VERSION 5.7 ;
  NOWIREEXTENSIONATPIN ON ;
  DIVIDERCHAR "/" ;
  BUSBITCHARS "[]" ;
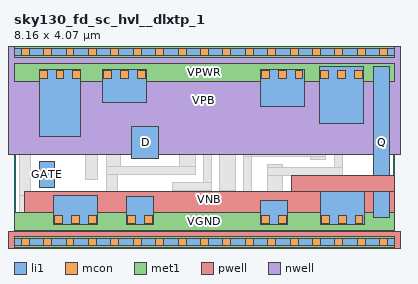
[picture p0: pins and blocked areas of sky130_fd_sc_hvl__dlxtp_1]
MACRO sky130_fd_sc_hvl__dlxtp_1
  CLASS BLOCK ;
  FOREIGN sky130_fd_sc_hvl__dlxtp_1 ;
  ORIGIN 0.000 0.000 ;
  SIZE 8.160 BY 4.070 ;
  PIN D
    ANTENNAGATEAREA 0.585000 ;
    PORT
      LAYER li1 ;
        RECT 2.525 1.795 3.100 2.465 ;
    END
  END D
  PIN GATE
    ANTENNAGATEAREA 0.585000 ;
    PORT
      LAYER li1 ;
        RECT 0.540 1.175 0.870 1.725 ;
    END
  END GATE
  PIN VGND
    USE GROUND ;
    PORT
      LAYER li1 ;
        RECT 0.845 0.365 1.795 0.995 ;
        RECT 2.405 0.365 2.995 0.975 ;
        RECT 5.270 0.365 5.860 0.895 ;
        RECT 6.555 0.365 7.505 1.245 ;
      LAYER mcon ;
        RECT 0.875 0.395 1.045 0.565 ;
        RECT 1.235 0.395 1.405 0.565 ;
        RECT 1.595 0.395 1.765 0.565 ;
        RECT 2.435 0.395 2.605 0.565 ;
        RECT 2.795 0.395 2.965 0.565 ;
        RECT 5.300 0.395 5.470 0.565 ;
        RECT 5.660 0.395 5.830 0.565 ;
        RECT 6.585 0.395 6.755 0.565 ;
        RECT 6.945 0.395 7.115 0.565 ;
        RECT 7.305 0.395 7.475 0.565 ;
      LAYER met1 ;
        RECT 0.000 0.255 8.160 0.625 ;
    END
  END VGND
  PIN VNB
    ANTENNADIFFAREA 1.387200 ;
    PORT
      LAYER pwell ;
        RECT 5.955 1.085 8.140 1.415 ;
        RECT 0.225 0.215 8.140 1.085 ;
        RECT -0.130 -0.215 8.290 0.215 ;
      LAYER li1 ;
        RECT 0.000 -0.085 8.160 0.085 ;
      LAYER mcon ;
        RECT 0.155 -0.085 0.325 0.085 ;
        RECT 0.635 -0.085 0.805 0.085 ;
        RECT 1.115 -0.085 1.285 0.085 ;
        RECT 1.595 -0.085 1.765 0.085 ;
        RECT 2.075 -0.085 2.245 0.085 ;
        RECT 2.555 -0.085 2.725 0.085 ;
        RECT 3.035 -0.085 3.205 0.085 ;
        RECT 3.515 -0.085 3.685 0.085 ;
        RECT 3.995 -0.085 4.165 0.085 ;
        RECT 4.475 -0.085 4.645 0.085 ;
        RECT 4.955 -0.085 5.125 0.085 ;
        RECT 5.435 -0.085 5.605 0.085 ;
        RECT 5.915 -0.085 6.085 0.085 ;
        RECT 6.395 -0.085 6.565 0.085 ;
        RECT 6.875 -0.085 7.045 0.085 ;
        RECT 7.355 -0.085 7.525 0.085 ;
        RECT 7.835 -0.085 8.005 0.085 ;
      LAYER met1 ;
        RECT 0.000 -0.115 8.160 0.115 ;
    END
  END VNB
  PIN VPB
    ANTENNADIFFAREA 1.387200 ;
    PORT
      LAYER nwell ;
        RECT -0.330 1.885 8.490 4.485 ;
      LAYER li1 ;
        RECT 0.000 3.985 8.160 4.155 ;
      LAYER mcon ;
        RECT 0.155 3.985 0.325 4.155 ;
        RECT 0.635 3.985 0.805 4.155 ;
        RECT 1.115 3.985 1.285 4.155 ;
        RECT 1.595 3.985 1.765 4.155 ;
        RECT 2.075 3.985 2.245 4.155 ;
        RECT 2.555 3.985 2.725 4.155 ;
        RECT 3.035 3.985 3.205 4.155 ;
        RECT 3.515 3.985 3.685 4.155 ;
        RECT 3.995 3.985 4.165 4.155 ;
        RECT 4.475 3.985 4.645 4.155 ;
        RECT 4.955 3.985 5.125 4.155 ;
        RECT 5.435 3.985 5.605 4.155 ;
        RECT 5.915 3.985 6.085 4.155 ;
        RECT 6.395 3.985 6.565 4.155 ;
        RECT 6.875 3.985 7.045 4.155 ;
        RECT 7.355 3.985 7.525 4.155 ;
        RECT 7.835 3.985 8.005 4.155 ;
      LAYER met1 ;
        RECT 0.000 3.955 8.160 4.185 ;
    END
  END VPB
  PIN VPWR
    USE POWER ;
    PORT
      LAYER li1 ;
        RECT 0.540 2.255 1.430 3.705 ;
        RECT 1.890 2.995 2.840 3.705 ;
        RECT 5.270 2.895 6.220 3.705 ;
        RECT 6.535 2.535 7.485 3.755 ;
      LAYER mcon ;
        RECT 0.540 3.505 0.710 3.675 ;
        RECT 0.900 3.505 1.070 3.675 ;
        RECT 1.260 3.505 1.430 3.675 ;
        RECT 1.920 3.505 2.090 3.675 ;
        RECT 2.280 3.505 2.450 3.675 ;
        RECT 2.640 3.505 2.810 3.675 ;
        RECT 5.300 3.505 5.470 3.675 ;
        RECT 5.660 3.505 5.830 3.675 ;
        RECT 6.020 3.505 6.190 3.675 ;
        RECT 6.565 3.505 6.735 3.675 ;
        RECT 6.925 3.505 7.095 3.675 ;
        RECT 7.285 3.505 7.455 3.675 ;
      LAYER met1 ;
        RECT 0.000 3.445 8.160 3.815 ;
    END
  END VPWR
  PIN Q
    ANTENNADIFFAREA 0.626250 ;
    PORT
      LAYER li1 ;
        RECT 7.700 0.515 8.050 3.755 ;
    END
  END Q
  OBS
      LAYER li1 ;
        RECT 3.020 3.635 4.050 3.805 ;
        RECT 0.110 2.075 0.360 2.985 ;
        RECT 3.020 2.815 3.190 3.635 ;
        RECT 1.610 2.645 3.190 2.815 ;
        RECT 3.370 2.895 3.700 3.455 ;
        RECT 1.610 2.075 1.780 2.645 ;
        RECT 1.960 2.195 2.290 2.465 ;
        RECT 0.110 2.015 1.780 2.075 ;
        RECT 0.110 1.905 1.795 2.015 ;
        RECT 0.110 0.995 0.360 1.905 ;
        RECT 1.540 1.345 1.795 1.905 ;
        RECT 1.975 1.615 2.290 2.195 ;
        RECT 3.370 2.335 3.540 2.895 ;
        RECT 3.880 2.715 4.050 3.635 ;
        RECT 4.230 3.065 4.480 3.725 ;
        RECT 4.230 2.895 5.090 3.065 ;
        RECT 3.720 2.515 4.740 2.715 ;
        RECT 3.370 2.165 4.230 2.335 ;
        RECT 3.550 1.615 3.880 1.985 ;
        RECT 1.975 1.445 3.880 1.615 ;
        RECT 0.110 0.495 0.665 0.995 ;
        RECT 1.975 0.515 2.225 1.445 ;
        RECT 4.060 1.265 4.230 2.165 ;
        RECT 3.385 1.095 4.230 1.265 ;
        RECT 4.410 1.095 4.740 2.515 ;
        RECT 4.920 2.005 5.090 2.895 ;
        RECT 6.025 2.355 6.355 2.675 ;
        RECT 6.025 2.185 7.030 2.355 ;
        RECT 4.920 1.835 6.680 2.005 ;
        RECT 3.385 0.995 3.555 1.095 ;
        RECT 3.225 0.495 3.555 0.995 ;
        RECT 4.920 0.915 5.090 1.835 ;
        RECT 6.350 1.775 6.680 1.835 ;
        RECT 5.430 1.595 5.760 1.655 ;
        RECT 6.860 1.595 7.030 2.185 ;
        RECT 5.430 1.425 7.030 1.595 ;
        RECT 5.430 1.075 5.760 1.425 ;
        RECT 4.005 0.745 5.090 0.915 ;
        RECT 6.045 0.845 6.375 1.425 ;
        RECT 4.005 0.495 4.335 0.745 ;
  END
END sky130_fd_sc_hvl__dlxtp_1
END LIBRARY

